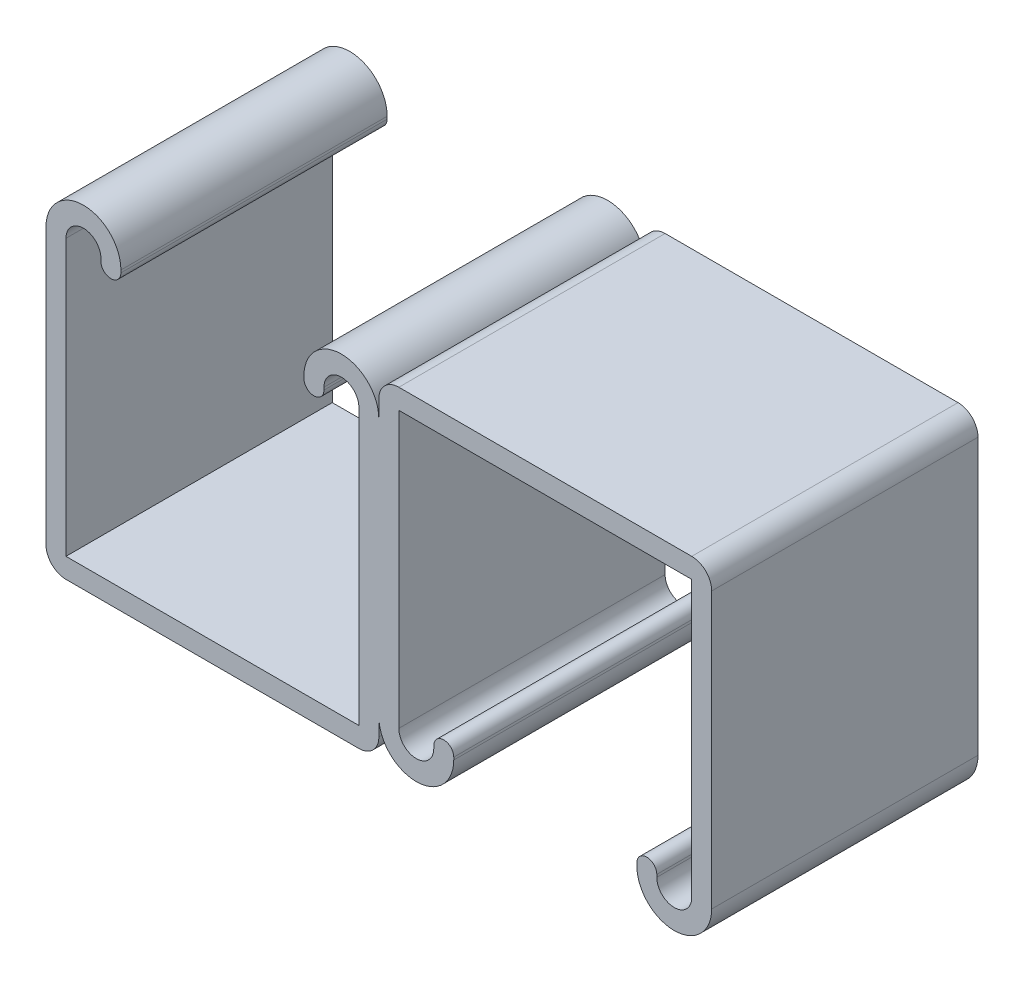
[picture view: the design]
ISO-10303-21;
HEADER;
FILE_DESCRIPTION(('STEP AP214'),'2;1');
FILE_NAME('part.step','',(''),(''),'','','');
FILE_SCHEMA(('AUTOMOTIVE_DESIGN { 1 0 10303 214 1 1 1 1 }'));
ENDSEC;
DATA;
#1=APPLICATION_CONTEXT('core data for automotive mechanical design processes');
#2=APPLICATION_PROTOCOL_DEFINITION('international standard','automotive_design',2000,#1);
#3=PRODUCT_CONTEXT('',#1,'mechanical');
#4=PRODUCT('Part','Part','',(#3));
#5=PRODUCT_RELATED_PRODUCT_CATEGORY('part','',(#4));
#6=PRODUCT_DEFINITION_FORMATION('','',#4);
#7=PRODUCT_DEFINITION_CONTEXT('part definition',#1,'design');
#8=PRODUCT_DEFINITION('design','',#6,#7);
#9=PRODUCT_DEFINITION_SHAPE('','',#8);
#10=(LENGTH_UNIT() NAMED_UNIT(*) SI_UNIT(.MILLI.,.METRE.));
#11=(NAMED_UNIT(*) PLANE_ANGLE_UNIT() SI_UNIT($,.RADIAN.));
#12=(NAMED_UNIT(*) SI_UNIT($,.STERADIAN.) SOLID_ANGLE_UNIT());
#13=UNCERTAINTY_MEASURE_WITH_UNIT(LENGTH_MEASURE(1.E-05),#10,'distance_accuracy_value','');
#14=(GEOMETRIC_REPRESENTATION_CONTEXT(3) GLOBAL_UNCERTAINTY_ASSIGNED_CONTEXT((#13)) GLOBAL_UNIT_ASSIGNED_CONTEXT((#10,
#11,#12)) REPRESENTATION_CONTEXT('',''));
#15=CARTESIAN_POINT('',(0.,0.,0.));
#16=DIRECTION('',(0.,0.,1.));
#17=DIRECTION('',(1.,0.,0.));
#18=AXIS2_PLACEMENT_3D('',#15,#16,#17);
#19=CARTESIAN_POINT('',(-28.178125,12.303125,12.7));
#20=DIRECTION('',(0.,0.,-1.));
#21=DIRECTION('',(-1.,0.,0.));
#22=AXIS2_PLACEMENT_3D('',#19,#20,#21);
#23=CYLINDRICAL_SURFACE('',#22,3.571875);
#24=CARTESIAN_POINT('',(-28.178125,12.303125,-12.7));
#25=DIRECTION('',(0.,0.,1.));
#26=DIRECTION('',(-1.,0.,0.));
#27=AXIS2_PLACEMENT_3D('',#24,#25,#26);
#28=CIRCLE('',#27,3.571875);
#29=CARTESIAN_POINT('',(-24.60625,12.303125,-12.7));
#30=VERTEX_POINT('',#29);
#31=CARTESIAN_POINT('',(-31.75,12.303125,-12.7));
#32=VERTEX_POINT('',#31);
#33=EDGE_CURVE('E300',#30,#32,#28,.T.);
#34=ORIENTED_EDGE('',*,*,#33,.T.);
#35=DIRECTION('',(0.,0.,-1.));
#36=VECTOR('',#35,1.);
#37=CARTESIAN_POINT('',(-31.75,12.303125,12.7));
#38=LINE('',#37,#36);
#39=CARTESIAN_POINT('',(-31.75,12.303125,12.7));
#40=VERTEX_POINT('',#39);
#41=EDGE_CURVE('E11',#40,#32,#38,.T.);
#42=ORIENTED_EDGE('',*,*,#41,.F.);
#43=CARTESIAN_POINT('',(-28.178125,12.303125,12.7));
#44=DIRECTION('',(0.,0.,1.));
#45=DIRECTION('',(-1.,0.,0.));
#46=AXIS2_PLACEMENT_3D('',#43,#44,#45);
#47=CIRCLE('',#46,3.571875);
#48=CARTESIAN_POINT('',(-24.60625,12.303125,12.7));
#49=VERTEX_POINT('',#48);
#50=EDGE_CURVE('E306',#49,#40,#47,.T.);
#51=ORIENTED_EDGE('',*,*,#50,.F.);
#52=DIRECTION('',(0.,0.,-1.));
#53=VECTOR('',#52,1.);
#54=CARTESIAN_POINT('',(-24.60625,12.303125,12.7));
#55=LINE('',#54,#53);
#56=EDGE_CURVE('E341',#49,#30,#55,.T.);
#57=ORIENTED_EDGE('',*,*,#56,.T.);
#58=EDGE_LOOP('',(#34,#42,#51,#57));
#59=FACE_BOUND('',#58,.T.);
#60=ADVANCED_FACE('F39',(#59),#23,.T.);
#61=CARTESIAN_POINT('',(-31.75,12.303125,12.7));
#62=DIRECTION('',(1.,0.,0.));
#63=DIRECTION('',(0.,1.,0.));
#64=AXIS2_PLACEMENT_3D('',#61,#62,#63);
#65=PLANE('',#64);
#66=DIRECTION('',(0.,-1.,0.));
#67=VECTOR('',#66,1.);
#68=CARTESIAN_POINT('',(-31.75,12.303125,-12.7));
#69=LINE('',#68,#67);
#70=CARTESIAN_POINT('',(-31.75,-13.97,-12.7));
#71=VERTEX_POINT('',#70);
#72=EDGE_CURVE('E297',#32,#71,#69,.T.);
#73=ORIENTED_EDGE('',*,*,#72,.T.);
#74=DIRECTION('',(0.,0.,-1.));
#75=VECTOR('',#74,1.);
#76=CARTESIAN_POINT('',(-31.75,-13.97,12.7));
#77=LINE('',#76,#75);
#78=CARTESIAN_POINT('',(-31.75,-13.97,12.7));
#79=VERTEX_POINT('',#78);
#80=EDGE_CURVE('E46',#79,#71,#77,.T.);
#81=ORIENTED_EDGE('',*,*,#80,.F.);
#82=DIRECTION('',(0.,-1.,0.));
#83=VECTOR('',#82,1.);
#84=CARTESIAN_POINT('',(-31.75,12.303125,12.7));
#85=LINE('',#84,#83);
#86=EDGE_CURVE('E308',#40,#79,#85,.T.);
#87=ORIENTED_EDGE('',*,*,#86,.F.);
#88=ORIENTED_EDGE('',*,*,#41,.T.);
#89=EDGE_LOOP('',(#73,#81,#87,#88));
#90=FACE_BOUND('',#89,.T.);
#91=ADVANCED_FACE('F443',(#90),#65,.F.);
#92=CARTESIAN_POINT('',(-29.845,-13.97,12.7));
#93=DIRECTION('',(0.,0.,-1.));
#94=DIRECTION('',(-1.,0.,0.));
#95=AXIS2_PLACEMENT_3D('',#92,#93,#94);
#96=CYLINDRICAL_SURFACE('',#95,1.90499999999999);
#97=CARTESIAN_POINT('',(-29.845,-13.97,-12.7));
#98=DIRECTION('',(0.,0.,1.));
#99=DIRECTION('',(-1.,0.,0.));
#100=AXIS2_PLACEMENT_3D('',#97,#98,#99);
#101=CIRCLE('',#100,1.90499999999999);
#102=CARTESIAN_POINT('',(-29.845,-15.875,-12.7));
#103=VERTEX_POINT('',#102);
#104=EDGE_CURVE('E342',#71,#103,#101,.T.);
#105=ORIENTED_EDGE('',*,*,#104,.T.);
#106=DIRECTION('',(0.,0.,-1.));
#107=VECTOR('',#106,1.);
#108=CARTESIAN_POINT('',(-29.845,-15.875,12.7));
#109=LINE('',#108,#107);
#110=CARTESIAN_POINT('',(-29.845,-15.875,12.7));
#111=VERTEX_POINT('',#110);
#112=EDGE_CURVE('E419',#111,#103,#109,.T.);
#113=ORIENTED_EDGE('',*,*,#112,.F.);
#114=CARTESIAN_POINT('',(-29.845,-13.97,12.7));
#115=DIRECTION('',(0.,0.,1.));
#116=DIRECTION('',(-1.,0.,0.));
#117=AXIS2_PLACEMENT_3D('',#114,#115,#116);
#118=CIRCLE('',#117,1.90499999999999);
#119=EDGE_CURVE('E311',#79,#111,#118,.T.);
#120=ORIENTED_EDGE('',*,*,#119,.F.);
#121=ORIENTED_EDGE('',*,*,#80,.T.);
#122=EDGE_LOOP('',(#105,#113,#120,#121));
#123=FACE_BOUND('',#122,.T.);
#124=ADVANCED_FACE('F424',(#123),#96,.T.);
#125=CARTESIAN_POINT('',(-29.845,-15.875,12.7));
#126=DIRECTION('',(0.,1.,0.));
#127=DIRECTION('',(0.,0.,1.));
#128=AXIS2_PLACEMENT_3D('',#125,#126,#127);
#129=PLANE('',#128);
#130=DIRECTION('',(1.,0.,0.));
#131=VECTOR('',#130,1.);
#132=CARTESIAN_POINT('',(-29.845,-15.875,-12.7));
#133=LINE('',#132,#131);
#134=CARTESIAN_POINT('',(-1.905,-15.875,-12.7));
#135=VERTEX_POINT('',#134);
#136=EDGE_CURVE('E350',#103,#135,#133,.T.);
#137=ORIENTED_EDGE('',*,*,#136,.T.);
#138=DIRECTION('',(0.,0.,-1.));
#139=VECTOR('',#138,1.);
#140=CARTESIAN_POINT('',(-1.905,-15.875,12.7));
#141=LINE('',#140,#139);
#142=CARTESIAN_POINT('',(-1.905,-15.875,12.7));
#143=VERTEX_POINT('',#142);
#144=EDGE_CURVE('E411',#143,#135,#141,.T.);
#145=ORIENTED_EDGE('',*,*,#144,.F.);
#146=DIRECTION('',(1.,0.,0.));
#147=VECTOR('',#146,1.);
#148=CARTESIAN_POINT('',(-29.845,-15.875,12.7));
#149=LINE('',#148,#147);
#150=EDGE_CURVE('E312',#111,#143,#149,.T.);
#151=ORIENTED_EDGE('',*,*,#150,.F.);
#152=ORIENTED_EDGE('',*,*,#112,.T.);
#153=EDGE_LOOP('',(#137,#145,#151,#152));
#154=FACE_BOUND('',#153,.T.);
#155=ADVANCED_FACE('F434',(#154),#129,.F.);
#156=CARTESIAN_POINT('',(-1.905,-13.97,12.7));
#157=DIRECTION('',(0.,0.,-1.));
#158=DIRECTION('',(-1.,0.,0.));
#159=AXIS2_PLACEMENT_3D('',#156,#157,#158);
#160=CYLINDRICAL_SURFACE('',#159,1.905);
#161=CARTESIAN_POINT('',(-1.905,-13.97,-12.7));
#162=DIRECTION('',(0.,0.,1.));
#163=DIRECTION('',(1.,0.,0.));
#164=AXIS2_PLACEMENT_3D('',#161,#162,#163);
#165=CIRCLE('',#164,1.905);
#166=CARTESIAN_POINT('',(0.,-13.97,-12.7));
#167=VERTEX_POINT('',#166);
#168=EDGE_CURVE('E349',#135,#167,#165,.T.);
#169=ORIENTED_EDGE('',*,*,#168,.T.);
#170=DIRECTION('',(0.,0.,-1.));
#171=VECTOR('',#170,1.);
#172=CARTESIAN_POINT('',(0.,-13.97,12.7));
#173=LINE('',#172,#171);
#174=CARTESIAN_POINT('',(0.,-13.97,12.7));
#175=VERTEX_POINT('',#174);
#176=EDGE_CURVE('E413',#175,#167,#173,.T.);
#177=ORIENTED_EDGE('',*,*,#176,.F.);
#178=CARTESIAN_POINT('',(-1.905,-13.97,12.7));
#179=DIRECTION('',(0.,0.,1.));
#180=DIRECTION('',(1.,0.,0.));
#181=AXIS2_PLACEMENT_3D('',#178,#179,#180);
#182=CIRCLE('',#181,1.905);
#183=EDGE_CURVE('E314',#143,#175,#182,.T.);
#184=ORIENTED_EDGE('',*,*,#183,.F.);
#185=ORIENTED_EDGE('',*,*,#144,.T.);
#186=EDGE_LOOP('',(#169,#177,#184,#185));
#187=FACE_BOUND('',#186,.T.);
#188=ADVANCED_FACE('F437',(#187),#160,.T.);
#189=CARTESIAN_POINT('',(0.,-13.97,12.7));
#190=DIRECTION('',(-1.,0.,0.));
#191=DIRECTION('',(0.,0.,1.));
#192=AXIS2_PLACEMENT_3D('',#189,#190,#191);
#193=PLANE('',#192);
#194=DIRECTION('',(0.,1.,0.));
#195=VECTOR('',#194,1.);
#196=CARTESIAN_POINT('',(0.,-13.97,-12.7));
#197=LINE('',#196,#195);
#198=CARTESIAN_POINT('',(0.,-12.303125,-12.7));
#199=VERTEX_POINT('',#198);
#200=EDGE_CURVE('E59',#167,#199,#197,.T.);
#201=ORIENTED_EDGE('',*,*,#200,.T.);
#202=DIRECTION('',(0.,0.,-1.));
#203=VECTOR('',#202,1.);
#204=CARTESIAN_POINT('',(0.,-12.303125,12.7));
#205=LINE('',#204,#203);
#206=CARTESIAN_POINT('',(0.,-12.303125,12.7));
#207=VERTEX_POINT('',#206);
#208=EDGE_CURVE('E52',#207,#199,#205,.T.);
#209=ORIENTED_EDGE('',*,*,#208,.F.);
#210=DIRECTION('',(0.,1.,0.));
#211=VECTOR('',#210,1.);
#212=CARTESIAN_POINT('',(0.,-13.97,12.7));
#213=LINE('',#212,#211);
#214=EDGE_CURVE('E320',#175,#207,#213,.T.);
#215=ORIENTED_EDGE('',*,*,#214,.F.);
#216=ORIENTED_EDGE('',*,*,#176,.T.);
#217=EDGE_LOOP('',(#201,#209,#215,#216));
#218=FACE_BOUND('',#217,.T.);
#219=ADVANCED_FACE('F650',(#218),#193,.F.);
#220=CARTESIAN_POINT('',(-3.571875,12.303125,12.7));
#221=DIRECTION('',(0.,0.,-1.));
#222=DIRECTION('',(-1.,0.,0.));
#223=AXIS2_PLACEMENT_3D('',#220,#221,#222);
#224=CYLINDRICAL_SURFACE('',#223,3.571875);
#225=CARTESIAN_POINT('',(-3.571875,12.303125,-12.7));
#226=DIRECTION('',(0.,0.,1.));
#227=DIRECTION('',(1.,0.,0.));
#228=AXIS2_PLACEMENT_3D('',#225,#226,#227);
#229=CIRCLE('',#228,3.571875);
#230=CARTESIAN_POINT('',(0.,12.303125,-12.7));
#231=VERTEX_POINT('',#230);
#232=CARTESIAN_POINT('',(-7.14375,12.303125,-12.7));
#233=VERTEX_POINT('',#232);
#234=EDGE_CURVE('E355',#231,#233,#229,.T.);
#235=ORIENTED_EDGE('',*,*,#234,.T.);
#236=DIRECTION('',(0.,0.,-1.));
#237=VECTOR('',#236,1.);
#238=CARTESIAN_POINT('',(-7.14375,12.303125,12.7));
#239=LINE('',#238,#237);
#240=CARTESIAN_POINT('',(-7.14375,12.303125,12.7));
#241=VERTEX_POINT('',#240);
#242=EDGE_CURVE('E406',#241,#233,#239,.T.);
#243=ORIENTED_EDGE('',*,*,#242,.F.);
#244=CARTESIAN_POINT('',(-3.571875,12.303125,12.7));
#245=DIRECTION('',(0.,0.,1.));
#246=DIRECTION('',(1.,0.,0.));
#247=AXIS2_PLACEMENT_3D('',#244,#245,#246);
#248=CIRCLE('',#247,3.571875);
#249=CARTESIAN_POINT('',(0.,12.303125,12.7));
#250=VERTEX_POINT('',#249);
#251=EDGE_CURVE('E316',#250,#241,#248,.T.);
#252=ORIENTED_EDGE('',*,*,#251,.F.);
#253=DIRECTION('',(0.,0.,-1.));
#254=VECTOR('',#253,1.);
#255=CARTESIAN_POINT('',(0.,12.303125,12.7));
#256=LINE('',#255,#254);
#257=EDGE_CURVE('E407',#250,#231,#256,.T.);
#258=ORIENTED_EDGE('',*,*,#257,.T.);
#259=EDGE_LOOP('',(#235,#243,#252,#258));
#260=FACE_BOUND('',#259,.T.);
#261=ADVANCED_FACE('F503',(#260),#224,.T.);
#262=CARTESIAN_POINT('',(-7.14375,12.303125,12.7));
#263=DIRECTION('',(1.,0.,0.));
#264=DIRECTION('',(0.,1.,0.));
#265=AXIS2_PLACEMENT_3D('',#262,#263,#264);
#266=PLANE('',#265);
#267=DIRECTION('',(0.,-1.,0.));
#268=VECTOR('',#267,1.);
#269=CARTESIAN_POINT('',(-7.14375,12.303125,-12.7));
#270=LINE('',#269,#268);
#271=CARTESIAN_POINT('',(-7.14375,12.065,-12.7));
#272=VERTEX_POINT('',#271);
#273=EDGE_CURVE('E351',#233,#272,#270,.T.);
#274=ORIENTED_EDGE('',*,*,#273,.T.);
#275=DIRECTION('',(0.,0.,-1.));
#276=VECTOR('',#275,1.);
#277=CARTESIAN_POINT('',(-7.14375,12.065,12.7));
#278=LINE('',#277,#276);
#279=CARTESIAN_POINT('',(-7.14375,12.065,12.7));
#280=VERTEX_POINT('',#279);
#281=EDGE_CURVE('E404',#280,#272,#278,.T.);
#282=ORIENTED_EDGE('',*,*,#281,.F.);
#283=DIRECTION('',(0.,-1.,0.));
#284=VECTOR('',#283,1.);
#285=CARTESIAN_POINT('',(-7.14375,12.303125,12.7));
#286=LINE('',#285,#284);
#287=EDGE_CURVE('E324',#241,#280,#286,.T.);
#288=ORIENTED_EDGE('',*,*,#287,.F.);
#289=ORIENTED_EDGE('',*,*,#242,.T.);
#290=EDGE_LOOP('',(#274,#282,#288,#289));
#291=FACE_BOUND('',#290,.T.);
#292=ADVANCED_FACE('F499',(#291),#266,.F.);
#293=CARTESIAN_POINT('',(-6.19125,12.065,12.7));
#294=DIRECTION('',(0.,0.,-1.));
#295=DIRECTION('',(-1.,0.,0.));
#296=AXIS2_PLACEMENT_3D('',#293,#294,#295);
#297=CYLINDRICAL_SURFACE('',#296,0.9525);
#298=CARTESIAN_POINT('',(-6.19125,12.065,-12.7));
#299=DIRECTION('',(0.,0.,1.));
#300=DIRECTION('',(1.,0.,0.));
#301=AXIS2_PLACEMENT_3D('',#298,#299,#300);
#302=CIRCLE('',#301,0.9525);
#303=CARTESIAN_POINT('',(-5.23875,12.065,-12.7));
#304=VERTEX_POINT('',#303);
#305=EDGE_CURVE('E358',#272,#304,#302,.T.);
#306=ORIENTED_EDGE('',*,*,#305,.T.);
#307=DIRECTION('',(0.,0.,-1.));
#308=VECTOR('',#307,1.);
#309=CARTESIAN_POINT('',(-5.23875,12.065,12.7));
#310=LINE('',#309,#308);
#311=CARTESIAN_POINT('',(-5.23875,12.065,12.7));
#312=VERTEX_POINT('',#311);
#313=EDGE_CURVE('E402',#312,#304,#310,.T.);
#314=ORIENTED_EDGE('',*,*,#313,.F.);
#315=CARTESIAN_POINT('',(-6.19125,12.065,12.7));
#316=DIRECTION('',(0.,0.,1.));
#317=DIRECTION('',(1.,0.,0.));
#318=AXIS2_PLACEMENT_3D('',#315,#316,#317);
#319=CIRCLE('',#318,0.9525);
#320=EDGE_CURVE('E325',#280,#312,#319,.T.);
#321=ORIENTED_EDGE('',*,*,#320,.F.);
#322=ORIENTED_EDGE('',*,*,#281,.T.);
#323=EDGE_LOOP('',(#306,#314,#321,#322));
#324=FACE_BOUND('',#323,.T.);
#325=ADVANCED_FACE('F492',(#324),#297,.T.);
#326=CARTESIAN_POINT('',(-5.23875,12.303125,12.7));
#327=DIRECTION('',(-1.,0.,0.));
#328=DIRECTION('',(0.,-1.,0.));
#329=AXIS2_PLACEMENT_3D('',#326,#327,#328);
#330=PLANE('',#329);
#331=DIRECTION('',(0.,1.,0.));
#332=VECTOR('',#331,1.);
#333=CARTESIAN_POINT('',(-5.23875,12.303125,-12.7));
#334=LINE('',#333,#332);
#335=CARTESIAN_POINT('',(-5.23875,12.303125,-12.7));
#336=VERTEX_POINT('',#335);
#337=EDGE_CURVE('E356',#304,#336,#334,.T.);
#338=ORIENTED_EDGE('',*,*,#337,.T.);
#339=DIRECTION('',(0.,0.,-1.));
#340=VECTOR('',#339,1.);
#341=CARTESIAN_POINT('',(-5.23875,12.303125,12.7));
#342=LINE('',#341,#340);
#343=CARTESIAN_POINT('',(-5.23875,12.303125,12.7));
#344=VERTEX_POINT('',#343);
#345=EDGE_CURVE('E399',#344,#336,#342,.T.);
#346=ORIENTED_EDGE('',*,*,#345,.F.);
#347=DIRECTION('',(0.,1.,0.));
#348=VECTOR('',#347,1.);
#349=CARTESIAN_POINT('',(-5.23875,12.303125,12.7));
#350=LINE('',#349,#348);
#351=EDGE_CURVE('E322',#312,#344,#350,.T.);
#352=ORIENTED_EDGE('',*,*,#351,.F.);
#353=ORIENTED_EDGE('',*,*,#313,.T.);
#354=EDGE_LOOP('',(#338,#346,#352,#353));
#355=FACE_BOUND('',#354,.T.);
#356=ADVANCED_FACE('F489',(#355),#330,.F.);
#357=CARTESIAN_POINT('',(-3.571875,12.303125,12.7));
#358=DIRECTION('',(0.,0.,-1.));
#359=DIRECTION('',(-1.,0.,0.));
#360=AXIS2_PLACEMENT_3D('',#357,#358,#359);
#361=CYLINDRICAL_SURFACE('',#360,1.666875);
#362=CARTESIAN_POINT('',(-3.571875,12.303125,-12.7));
#363=DIRECTION('',(0.,0.,-1.));
#364=DIRECTION('',(1.,0.,0.));
#365=AXIS2_PLACEMENT_3D('',#362,#363,#364);
#366=CIRCLE('',#365,1.666875);
#367=CARTESIAN_POINT('',(-1.905,12.303125,-12.7));
#368=VERTEX_POINT('',#367);
#369=EDGE_CURVE('E359',#336,#368,#366,.T.);
#370=ORIENTED_EDGE('',*,*,#369,.T.);
#371=DIRECTION('',(0.,0.,-1.));
#372=VECTOR('',#371,1.);
#373=CARTESIAN_POINT('',(-1.905,12.303125,12.7));
#374=LINE('',#373,#372);
#375=CARTESIAN_POINT('',(-1.905,12.303125,12.7));
#376=VERTEX_POINT('',#375);
#377=EDGE_CURVE('E391',#376,#368,#374,.T.);
#378=ORIENTED_EDGE('',*,*,#377,.F.);
#379=CARTESIAN_POINT('',(-3.571875,12.303125,12.7));
#380=DIRECTION('',(0.,0.,-1.));
#381=DIRECTION('',(1.,0.,0.));
#382=AXIS2_PLACEMENT_3D('',#379,#380,#381);
#383=CIRCLE('',#382,1.666875);
#384=EDGE_CURVE('E330',#344,#376,#383,.T.);
#385=ORIENTED_EDGE('',*,*,#384,.F.);
#386=ORIENTED_EDGE('',*,*,#345,.T.);
#387=EDGE_LOOP('',(#370,#378,#385,#386));
#388=FACE_BOUND('',#387,.T.);
#389=ADVANCED_FACE('F488',(#388),#361,.F.);
#390=CARTESIAN_POINT('',(-1.905,-13.97,12.7));
#391=DIRECTION('',(1.,0.,0.));
#392=DIRECTION('',(0.,0.,-1.));
#393=AXIS2_PLACEMENT_3D('',#390,#391,#392);
#394=PLANE('',#393);
#395=DIRECTION('',(0.,-1.,0.));
#396=VECTOR('',#395,1.);
#397=CARTESIAN_POINT('',(-1.905,-13.97,-12.7));
#398=LINE('',#397,#396);
#399=CARTESIAN_POINT('',(-1.905,-13.97,-12.7));
#400=VERTEX_POINT('',#399);
#401=EDGE_CURVE('E365',#368,#400,#398,.T.);
#402=ORIENTED_EDGE('',*,*,#401,.T.);
#403=DIRECTION('',(0.,0.,-1.));
#404=VECTOR('',#403,1.);
#405=CARTESIAN_POINT('',(-1.905,-13.97,12.7));
#406=LINE('',#405,#404);
#407=CARTESIAN_POINT('',(-1.905,-13.97,12.7));
#408=VERTEX_POINT('',#407);
#409=EDGE_CURVE('E395',#408,#400,#406,.T.);
#410=ORIENTED_EDGE('',*,*,#409,.F.);
#411=DIRECTION('',(0.,-1.,0.));
#412=VECTOR('',#411,1.);
#413=CARTESIAN_POINT('',(-1.905,-13.97,12.7));
#414=LINE('',#413,#412);
#415=EDGE_CURVE('E329',#376,#408,#414,.T.);
#416=ORIENTED_EDGE('',*,*,#415,.F.);
#417=ORIENTED_EDGE('',*,*,#377,.T.);
#418=EDGE_LOOP('',(#402,#410,#416,#417));
#419=FACE_BOUND('',#418,.T.);
#420=ADVANCED_FACE('F482',(#419),#394,.F.);
#421=CARTESIAN_POINT('',(-29.845,-13.97,12.7));
#422=DIRECTION('',(0.,-1.,0.));
#423=DIRECTION('',(0.,0.,-1.));
#424=AXIS2_PLACEMENT_3D('',#421,#422,#423);
#425=PLANE('',#424);
#426=DIRECTION('',(-1.,0.,0.));
#427=VECTOR('',#426,1.);
#428=CARTESIAN_POINT('',(-29.845,-13.97,-12.7));
#429=LINE('',#428,#427);
#430=CARTESIAN_POINT('',(-29.845,-13.97,-12.7));
#431=VERTEX_POINT('',#430);
#432=EDGE_CURVE('E364',#400,#431,#429,.T.);
#433=ORIENTED_EDGE('',*,*,#432,.T.);
#434=DIRECTION('',(0.,0.,-1.));
#435=VECTOR('',#434,1.);
#436=CARTESIAN_POINT('',(-29.845,-13.97,12.7));
#437=LINE('',#436,#435);
#438=CARTESIAN_POINT('',(-29.845,-13.97,12.7));
#439=VERTEX_POINT('',#438);
#440=EDGE_CURVE('E388',#439,#431,#437,.T.);
#441=ORIENTED_EDGE('',*,*,#440,.F.);
#442=DIRECTION('',(-1.,0.,0.));
#443=VECTOR('',#442,1.);
#444=CARTESIAN_POINT('',(-29.845,-13.97,12.7));
#445=LINE('',#444,#443);
#446=EDGE_CURVE('E332',#408,#439,#445,.T.);
#447=ORIENTED_EDGE('',*,*,#446,.F.);
#448=ORIENTED_EDGE('',*,*,#409,.T.);
#449=EDGE_LOOP('',(#433,#441,#447,#448));
#450=FACE_BOUND('',#449,.T.);
#451=ADVANCED_FACE('F472',(#450),#425,.F.);
#452=CARTESIAN_POINT('',(-29.845,12.303125,12.7));
#453=DIRECTION('',(-1.,0.,0.));
#454=DIRECTION('',(0.,-1.,0.));
#455=AXIS2_PLACEMENT_3D('',#452,#453,#454);
#456=PLANE('',#455);
#457=DIRECTION('',(0.,1.,0.));
#458=VECTOR('',#457,1.);
#459=CARTESIAN_POINT('',(-29.845,12.303125,-12.7));
#460=LINE('',#459,#458);
#461=CARTESIAN_POINT('',(-29.845,12.303125,-12.7));
#462=VERTEX_POINT('',#461);
#463=EDGE_CURVE('E366',#431,#462,#460,.T.);
#464=ORIENTED_EDGE('',*,*,#463,.T.);
#465=DIRECTION('',(0.,0.,-1.));
#466=VECTOR('',#465,1.);
#467=CARTESIAN_POINT('',(-29.845,12.303125,12.7));
#468=LINE('',#467,#466);
#469=CARTESIAN_POINT('',(-29.845,12.303125,12.7));
#470=VERTEX_POINT('',#469);
#471=EDGE_CURVE('E389',#470,#462,#468,.T.);
#472=ORIENTED_EDGE('',*,*,#471,.F.);
#473=DIRECTION('',(0.,1.,0.));
#474=VECTOR('',#473,1.);
#475=CARTESIAN_POINT('',(-29.845,12.303125,12.7));
#476=LINE('',#475,#474);
#477=EDGE_CURVE('E334',#439,#470,#476,.T.);
#478=ORIENTED_EDGE('',*,*,#477,.F.);
#479=ORIENTED_EDGE('',*,*,#440,.T.);
#480=EDGE_LOOP('',(#464,#472,#478,#479));
#481=FACE_BOUND('',#480,.T.);
#482=ADVANCED_FACE('F474',(#481),#456,.F.);
#483=CARTESIAN_POINT('',(-28.178125,12.303125,12.7));
#484=DIRECTION('',(0.,0.,-1.));
#485=DIRECTION('',(-1.,0.,0.));
#486=AXIS2_PLACEMENT_3D('',#483,#484,#485);
#487=CYLINDRICAL_SURFACE('',#486,1.666875);
#488=CARTESIAN_POINT('',(-28.178125,12.303125,-12.7));
#489=DIRECTION('',(0.,0.,-1.));
#490=DIRECTION('',(-1.,0.,0.));
#491=AXIS2_PLACEMENT_3D('',#488,#489,#490);
#492=CIRCLE('',#491,1.666875);
#493=CARTESIAN_POINT('',(-26.51125,12.303125,-12.7));
#494=VERTEX_POINT('',#493);
#495=EDGE_CURVE('E368',#462,#494,#492,.T.);
#496=ORIENTED_EDGE('',*,*,#495,.T.);
#497=DIRECTION('',(0.,0.,-1.));
#498=VECTOR('',#497,1.);
#499=CARTESIAN_POINT('',(-26.51125,12.303125,12.7));
#500=LINE('',#499,#498);
#501=CARTESIAN_POINT('',(-26.51125,12.303125,12.7));
#502=VERTEX_POINT('',#501);
#503=EDGE_CURVE('E384',#502,#494,#500,.T.);
#504=ORIENTED_EDGE('',*,*,#503,.F.);
#505=CARTESIAN_POINT('',(-28.178125,12.303125,12.7));
#506=DIRECTION('',(0.,0.,-1.));
#507=DIRECTION('',(-1.,0.,0.));
#508=AXIS2_PLACEMENT_3D('',#505,#506,#507);
#509=CIRCLE('',#508,1.666875);
#510=EDGE_CURVE('E333',#470,#502,#509,.T.);
#511=ORIENTED_EDGE('',*,*,#510,.F.);
#512=ORIENTED_EDGE('',*,*,#471,.T.);
#513=EDGE_LOOP('',(#496,#504,#511,#512));
#514=FACE_BOUND('',#513,.T.);
#515=ADVANCED_FACE('F467',(#514),#487,.F.);
#516=CARTESIAN_POINT('',(-26.51125,12.303125,12.7));
#517=DIRECTION('',(1.,0.,0.));
#518=DIRECTION('',(0.,1.,0.));
#519=AXIS2_PLACEMENT_3D('',#516,#517,#518);
#520=PLANE('',#519);
#521=DIRECTION('',(0.,-1.,0.));
#522=VECTOR('',#521,1.);
#523=CARTESIAN_POINT('',(-26.51125,12.303125,-12.7));
#524=LINE('',#523,#522);
#525=CARTESIAN_POINT('',(-26.51125,12.065,-12.7));
#526=VERTEX_POINT('',#525);
#527=EDGE_CURVE('E369',#494,#526,#524,.T.);
#528=ORIENTED_EDGE('',*,*,#527,.T.);
#529=DIRECTION('',(0.,0.,-1.));
#530=VECTOR('',#529,1.);
#531=CARTESIAN_POINT('',(-26.51125,12.065,12.7));
#532=LINE('',#531,#530);
#533=CARTESIAN_POINT('',(-26.51125,12.065,12.7));
#534=VERTEX_POINT('',#533);
#535=EDGE_CURVE('E379',#534,#526,#532,.T.);
#536=ORIENTED_EDGE('',*,*,#535,.F.);
#537=DIRECTION('',(0.,-1.,0.));
#538=VECTOR('',#537,1.);
#539=CARTESIAN_POINT('',(-26.51125,12.303125,12.7));
#540=LINE('',#539,#538);
#541=EDGE_CURVE('E340',#502,#534,#540,.T.);
#542=ORIENTED_EDGE('',*,*,#541,.F.);
#543=ORIENTED_EDGE('',*,*,#503,.T.);
#544=EDGE_LOOP('',(#528,#536,#542,#543));
#545=FACE_BOUND('',#544,.T.);
#546=ADVANCED_FACE('F456',(#545),#520,.F.);
#547=CARTESIAN_POINT('',(-25.55875,12.065,12.7));
#548=DIRECTION('',(0.,0.,-1.));
#549=DIRECTION('',(-1.,0.,0.));
#550=AXIS2_PLACEMENT_3D('',#547,#548,#549);
#551=CYLINDRICAL_SURFACE('',#550,0.952500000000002);
#552=CARTESIAN_POINT('',(-25.55875,12.065,-12.7));
#553=DIRECTION('',(0.,0.,1.));
#554=DIRECTION('',(-1.,0.,0.));
#555=AXIS2_PLACEMENT_3D('',#552,#553,#554);
#556=CIRCLE('',#555,0.952500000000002);
#557=CARTESIAN_POINT('',(-24.60625,12.065,-12.7));
#558=VERTEX_POINT('',#557);
#559=EDGE_CURVE('E375',#526,#558,#556,.T.);
#560=ORIENTED_EDGE('',*,*,#559,.T.);
#561=DIRECTION('',(0.,0.,-1.));
#562=VECTOR('',#561,1.);
#563=CARTESIAN_POINT('',(-24.60625,12.065,12.7));
#564=LINE('',#563,#562);
#565=CARTESIAN_POINT('',(-24.60625,12.065,12.7));
#566=VERTEX_POINT('',#565);
#567=EDGE_CURVE('E380',#566,#558,#564,.T.);
#568=ORIENTED_EDGE('',*,*,#567,.F.);
#569=CARTESIAN_POINT('',(-25.55875,12.065,12.7));
#570=DIRECTION('',(0.,0.,1.));
#571=DIRECTION('',(-1.,0.,0.));
#572=AXIS2_PLACEMENT_3D('',#569,#570,#571);
#573=CIRCLE('',#572,0.952500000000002);
#574=EDGE_CURVE('E339',#534,#566,#573,.T.);
#575=ORIENTED_EDGE('',*,*,#574,.F.);
#576=ORIENTED_EDGE('',*,*,#535,.T.);
#577=EDGE_LOOP('',(#560,#568,#575,#576));
#578=FACE_BOUND('',#577,.T.);
#579=ADVANCED_FACE('F457',(#578),#551,.T.);
#580=CARTESIAN_POINT('',(-24.60625,12.303125,12.7));
#581=DIRECTION('',(-1.,0.,0.));
#582=DIRECTION('',(0.,-1.,0.));
#583=AXIS2_PLACEMENT_3D('',#580,#581,#582);
#584=PLANE('',#583);
#585=DIRECTION('',(0.,1.,0.));
#586=VECTOR('',#585,1.);
#587=CARTESIAN_POINT('',(-24.60625,12.303125,-12.7));
#588=LINE('',#587,#586);
#589=EDGE_CURVE('E307',#558,#30,#588,.T.);
#590=ORIENTED_EDGE('',*,*,#589,.T.);
#591=ORIENTED_EDGE('',*,*,#56,.F.);
#592=DIRECTION('',(0.,1.,0.));
#593=VECTOR('',#592,1.);
#594=CARTESIAN_POINT('',(-24.60625,12.303125,12.7));
#595=LINE('',#594,#593);
#596=EDGE_CURVE('E344',#566,#49,#595,.T.);
#597=ORIENTED_EDGE('',*,*,#596,.F.);
#598=ORIENTED_EDGE('',*,*,#567,.T.);
#599=EDGE_LOOP('',(#590,#591,#597,#598));
#600=FACE_BOUND('',#599,.T.);
#601=ADVANCED_FACE('F454',(#600),#584,.F.);
#602=CARTESIAN_POINT('',(-28.178125,12.303125,12.7));
#603=DIRECTION('',(0.,0.,-1.));
#604=DIRECTION('',(-1.,0.,0.));
#605=AXIS2_PLACEMENT_3D('',#602,#603,#604);
#606=PLANE('',#605);
#607=ORIENTED_EDGE('',*,*,#50,.T.);
#608=ORIENTED_EDGE('',*,*,#86,.T.);
#609=ORIENTED_EDGE('',*,*,#119,.T.);
#610=ORIENTED_EDGE('',*,*,#150,.T.);
#611=ORIENTED_EDGE('',*,*,#183,.T.);
#612=ORIENTED_EDGE('',*,*,#214,.T.);
#613=CARTESIAN_POINT('',(3.57187500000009,-12.303125,12.7));
#614=DIRECTION('',(0.,0.,1.));
#615=DIRECTION('',(-1.,0.,0.));
#616=AXIS2_PLACEMENT_3D('',#613,#614,#615);
#617=CIRCLE('',#616,3.571875);
#618=CARTESIAN_POINT('',(7.14375000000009,-12.3031249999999,12.7));
#619=VERTEX_POINT('',#618);
#620=EDGE_CURVE('E617',#207,#619,#617,.T.);
#621=ORIENTED_EDGE('',*,*,#620,.T.);
#622=DIRECTION('',(0.,1.,0.));
#623=VECTOR('',#622,1.);
#624=CARTESIAN_POINT('',(7.14375000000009,-12.3031249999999,12.7));
#625=LINE('',#624,#623);
#626=CARTESIAN_POINT('',(7.14375000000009,-12.065,12.7));
#627=VERTEX_POINT('',#626);
#628=EDGE_CURVE('E613',#619,#627,#625,.T.);
#629=ORIENTED_EDGE('',*,*,#628,.T.);
#630=CARTESIAN_POINT('',(6.19125000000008,-12.065,12.7));
#631=DIRECTION('',(0.,0.,1.));
#632=DIRECTION('',(-1.,0.,0.));
#633=AXIS2_PLACEMENT_3D('',#630,#631,#632);
#634=CIRCLE('',#633,0.9525);
#635=CARTESIAN_POINT('',(5.23875000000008,-12.065,12.7));
#636=VERTEX_POINT('',#635);
#637=EDGE_CURVE('E614',#627,#636,#634,.T.);
#638=ORIENTED_EDGE('',*,*,#637,.T.);
#639=DIRECTION('',(0.,-1.,0.));
#640=VECTOR('',#639,1.);
#641=CARTESIAN_POINT('',(5.23875000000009,-12.303125,12.7));
#642=LINE('',#641,#640);
#643=CARTESIAN_POINT('',(5.23875000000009,-12.303125,12.7));
#644=VERTEX_POINT('',#643);
#645=EDGE_CURVE('E612',#636,#644,#642,.T.);
#646=ORIENTED_EDGE('',*,*,#645,.T.);
#647=CARTESIAN_POINT('',(3.57187500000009,-12.303125,12.7));
#648=DIRECTION('',(0.,0.,-1.));
#649=DIRECTION('',(-1.,0.,0.));
#650=AXIS2_PLACEMENT_3D('',#647,#648,#649);
#651=CIRCLE('',#650,1.666875);
#652=CARTESIAN_POINT('',(1.90500000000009,-12.303125,12.7));
#653=VERTEX_POINT('',#652);
#654=EDGE_CURVE('E609',#644,#653,#651,.T.);
#655=ORIENTED_EDGE('',*,*,#654,.T.);
#656=DIRECTION('',(0.,1.,0.));
#657=VECTOR('',#656,1.);
#658=CARTESIAN_POINT('',(1.9049999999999,13.97,12.7));
#659=LINE('',#658,#657);
#660=CARTESIAN_POINT('',(1.9049999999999,13.97,12.7));
#661=VERTEX_POINT('',#660);
#662=EDGE_CURVE('E610',#653,#661,#659,.T.);
#663=ORIENTED_EDGE('',*,*,#662,.T.);
#664=DIRECTION('',(1.,0.,0.));
#665=VECTOR('',#664,1.);
#666=CARTESIAN_POINT('',(29.8449999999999,13.9700000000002,12.7));
#667=LINE('',#666,#665);
#668=CARTESIAN_POINT('',(29.8449999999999,13.9700000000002,12.7));
#669=VERTEX_POINT('',#668);
#670=EDGE_CURVE('E602',#661,#669,#667,.T.);
#671=ORIENTED_EDGE('',*,*,#670,.T.);
#672=DIRECTION('',(0.,-1.,0.));
#673=VECTOR('',#672,1.);
#674=CARTESIAN_POINT('',(29.8450000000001,-12.3031249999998,12.7));
#675=LINE('',#674,#673);
#676=CARTESIAN_POINT('',(29.8450000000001,-12.3031249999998,12.7));
#677=VERTEX_POINT('',#676);
#678=EDGE_CURVE('E605',#669,#677,#675,.T.);
#679=ORIENTED_EDGE('',*,*,#678,.T.);
#680=CARTESIAN_POINT('',(28.1781250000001,-12.3031249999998,12.7));
#681=DIRECTION('',(0.,0.,-1.));
#682=DIRECTION('',(1.,0.,0.));
#683=AXIS2_PLACEMENT_3D('',#680,#681,#682);
#684=CIRCLE('',#683,1.666875);
#685=CARTESIAN_POINT('',(26.5112500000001,-12.3031249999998,12.7));
#686=VERTEX_POINT('',#685);
#687=EDGE_CURVE('E604',#677,#686,#684,.T.);
#688=ORIENTED_EDGE('',*,*,#687,.T.);
#689=DIRECTION('',(0.,1.,0.));
#690=VECTOR('',#689,1.);
#691=CARTESIAN_POINT('',(26.5112500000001,-12.3031249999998,12.7));
#692=LINE('',#691,#690);
#693=CARTESIAN_POINT('',(26.5112500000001,-12.0649999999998,12.7));
#694=VERTEX_POINT('',#693);
#695=EDGE_CURVE('E599',#686,#694,#692,.T.);
#696=ORIENTED_EDGE('',*,*,#695,.T.);
#697=CARTESIAN_POINT('',(25.5587500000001,-12.0649999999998,12.7));
#698=DIRECTION('',(0.,0.,1.));
#699=DIRECTION('',(1.,0.,0.));
#700=AXIS2_PLACEMENT_3D('',#697,#698,#699);
#701=CIRCLE('',#700,0.952500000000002);
#702=CARTESIAN_POINT('',(24.6062500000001,-12.0649999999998,12.7));
#703=VERTEX_POINT('',#702);
#704=EDGE_CURVE('E600',#694,#703,#701,.T.);
#705=ORIENTED_EDGE('',*,*,#704,.T.);
#706=DIRECTION('',(0.,-1.,0.));
#707=VECTOR('',#706,1.);
#708=CARTESIAN_POINT('',(24.6062500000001,-12.3031249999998,12.7));
#709=LINE('',#708,#707);
#710=CARTESIAN_POINT('',(24.6062500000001,-12.3031249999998,12.7));
#711=VERTEX_POINT('',#710);
#712=EDGE_CURVE('E289',#703,#711,#709,.T.);
#713=ORIENTED_EDGE('',*,*,#712,.T.);
#714=CARTESIAN_POINT('',(28.1781250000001,-12.3031249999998,12.7));
#715=DIRECTION('',(0.,0.,1.));
#716=DIRECTION('',(1.,0.,0.));
#717=AXIS2_PLACEMENT_3D('',#714,#715,#716);
#718=CIRCLE('',#717,3.571875);
#719=CARTESIAN_POINT('',(31.7500000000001,-12.3031249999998,12.7));
#720=VERTEX_POINT('',#719);
#721=EDGE_CURVE('E285',#711,#720,#718,.T.);
#722=ORIENTED_EDGE('',*,*,#721,.T.);
#723=DIRECTION('',(0.,1.,0.));
#724=VECTOR('',#723,1.);
#725=CARTESIAN_POINT('',(31.7500000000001,-12.3031249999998,12.7));
#726=LINE('',#725,#724);
#727=CARTESIAN_POINT('',(31.7499999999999,13.9700000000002,12.7));
#728=VERTEX_POINT('',#727);
#729=EDGE_CURVE('E272',#720,#728,#726,.T.);
#730=ORIENTED_EDGE('',*,*,#729,.T.);
#731=CARTESIAN_POINT('',(29.8449999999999,13.9700000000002,12.7));
#732=DIRECTION('',(0.,0.,1.));
#733=DIRECTION('',(1.,0.,0.));
#734=AXIS2_PLACEMENT_3D('',#731,#732,#733);
#735=CIRCLE('',#734,1.90499999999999);
#736=CARTESIAN_POINT('',(29.8449999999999,15.8750000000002,12.7));
#737=VERTEX_POINT('',#736);
#738=EDGE_CURVE('E282',#728,#737,#735,.T.);
#739=ORIENTED_EDGE('',*,*,#738,.T.);
#740=DIRECTION('',(-1.,0.,0.));
#741=VECTOR('',#740,1.);
#742=CARTESIAN_POINT('',(29.8449999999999,15.8750000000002,12.7));
#743=LINE('',#742,#741);
#744=CARTESIAN_POINT('',(1.90499999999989,15.875,12.7));
#745=VERTEX_POINT('',#744);
#746=EDGE_CURVE('E590',#737,#745,#743,.T.);
#747=ORIENTED_EDGE('',*,*,#746,.T.);
#748=CARTESIAN_POINT('',(1.9049999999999,13.97,12.7));
#749=DIRECTION('',(0.,0.,1.));
#750=DIRECTION('',(-1.,0.,0.));
#751=AXIS2_PLACEMENT_3D('',#748,#749,#750);
#752=CIRCLE('',#751,1.905);
#753=CARTESIAN_POINT('',(0.,13.97,12.7));
#754=VERTEX_POINT('',#753);
#755=EDGE_CURVE('E625',#745,#754,#752,.T.);
#756=ORIENTED_EDGE('',*,*,#755,.T.);
#757=DIRECTION('',(0.,-1.,0.));
#758=VECTOR('',#757,1.);
#759=CARTESIAN_POINT('',(0.,13.97,12.7));
#760=LINE('',#759,#758);
#761=EDGE_CURVE('E620',#754,#250,#760,.T.);
#762=ORIENTED_EDGE('',*,*,#761,.T.);
#763=ORIENTED_EDGE('',*,*,#251,.T.);
#764=ORIENTED_EDGE('',*,*,#287,.T.);
#765=ORIENTED_EDGE('',*,*,#320,.T.);
#766=ORIENTED_EDGE('',*,*,#351,.T.);
#767=ORIENTED_EDGE('',*,*,#384,.T.);
#768=ORIENTED_EDGE('',*,*,#415,.T.);
#769=ORIENTED_EDGE('',*,*,#446,.T.);
#770=ORIENTED_EDGE('',*,*,#477,.T.);
#771=ORIENTED_EDGE('',*,*,#510,.T.);
#772=ORIENTED_EDGE('',*,*,#541,.T.);
#773=ORIENTED_EDGE('',*,*,#574,.T.);
#774=ORIENTED_EDGE('',*,*,#596,.T.);
#775=EDGE_LOOP('',(#607,#608,#609,#610,#611,#612,#621,#629,#638,#646,#655,#663,#671,#679,#688,
#696,#705,#713,#722,#730,#739,#747,#756,#762,#763,#764,#765,#766,#767,#768,#769,#770,#771,#772,
#773,#774));
#776=FACE_BOUND('',#775,.T.);
#777=ADVANCED_FACE('F287',(#776),#606,.F.);
#778=CARTESIAN_POINT('',(-28.178125,12.303125,-12.7));
#779=DIRECTION('',(0.,0.,-1.));
#780=DIRECTION('',(-1.,0.,0.));
#781=AXIS2_PLACEMENT_3D('',#778,#779,#780);
#782=PLANE('',#781);
#783=ORIENTED_EDGE('',*,*,#33,.F.);
#784=ORIENTED_EDGE('',*,*,#589,.F.);
#785=ORIENTED_EDGE('',*,*,#559,.F.);
#786=ORIENTED_EDGE('',*,*,#527,.F.);
#787=ORIENTED_EDGE('',*,*,#495,.F.);
#788=ORIENTED_EDGE('',*,*,#463,.F.);
#789=ORIENTED_EDGE('',*,*,#432,.F.);
#790=ORIENTED_EDGE('',*,*,#401,.F.);
#791=ORIENTED_EDGE('',*,*,#369,.F.);
#792=ORIENTED_EDGE('',*,*,#337,.F.);
#793=ORIENTED_EDGE('',*,*,#305,.F.);
#794=ORIENTED_EDGE('',*,*,#273,.F.);
#795=ORIENTED_EDGE('',*,*,#234,.F.);
#796=DIRECTION('',(0.,-1.,0.));
#797=VECTOR('',#796,1.);
#798=CARTESIAN_POINT('',(0.,13.97,-12.7));
#799=LINE('',#798,#797);
#800=CARTESIAN_POINT('',(0.,13.97,-12.7));
#801=VERTEX_POINT('',#800);
#802=EDGE_CURVE('E507',#801,#231,#799,.T.);
#803=ORIENTED_EDGE('',*,*,#802,.F.);
#804=CARTESIAN_POINT('',(1.9049999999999,13.97,-12.7));
#805=DIRECTION('',(0.,0.,1.));
#806=DIRECTION('',(-1.,0.,0.));
#807=AXIS2_PLACEMENT_3D('',#804,#805,#806);
#808=CIRCLE('',#807,1.905);
#809=CARTESIAN_POINT('',(1.90499999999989,15.875,-12.7));
#810=VERTEX_POINT('',#809);
#811=EDGE_CURVE('E509',#810,#801,#808,.T.);
#812=ORIENTED_EDGE('',*,*,#811,.F.);
#813=DIRECTION('',(-1.,0.,0.));
#814=VECTOR('',#813,1.);
#815=CARTESIAN_POINT('',(29.8449999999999,15.8750000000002,-12.7));
#816=LINE('',#815,#814);
#817=CARTESIAN_POINT('',(29.8449999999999,15.8750000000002,-12.7));
#818=VERTEX_POINT('',#817);
#819=EDGE_CURVE('E516',#818,#810,#816,.T.);
#820=ORIENTED_EDGE('',*,*,#819,.F.);
#821=CARTESIAN_POINT('',(29.8449999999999,13.9700000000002,-12.7));
#822=DIRECTION('',(0.,0.,1.));
#823=DIRECTION('',(1.,0.,0.));
#824=AXIS2_PLACEMENT_3D('',#821,#822,#823);
#825=CIRCLE('',#824,1.90499999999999);
#826=CARTESIAN_POINT('',(31.7499999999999,13.9700000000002,-12.7));
#827=VERTEX_POINT('',#826);
#828=EDGE_CURVE('E586',#827,#818,#825,.T.);
#829=ORIENTED_EDGE('',*,*,#828,.F.);
#830=DIRECTION('',(0.,1.,0.));
#831=VECTOR('',#830,1.);
#832=CARTESIAN_POINT('',(31.7500000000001,-12.3031249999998,-12.7));
#833=LINE('',#832,#831);
#834=CARTESIAN_POINT('',(31.7500000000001,-12.3031249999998,-12.7));
#835=VERTEX_POINT('',#834);
#836=EDGE_CURVE('E592',#835,#827,#833,.T.);
#837=ORIENTED_EDGE('',*,*,#836,.F.);
#838=CARTESIAN_POINT('',(28.1781250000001,-12.3031249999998,-12.7));
#839=DIRECTION('',(0.,0.,1.));
#840=DIRECTION('',(1.,0.,0.));
#841=AXIS2_PLACEMENT_3D('',#838,#839,#840);
#842=CIRCLE('',#841,3.571875);
#843=CARTESIAN_POINT('',(24.6062500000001,-12.3031249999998,-12.7));
#844=VERTEX_POINT('',#843);
#845=EDGE_CURVE('E298',#844,#835,#842,.T.);
#846=ORIENTED_EDGE('',*,*,#845,.F.);
#847=DIRECTION('',(0.,-1.,0.));
#848=VECTOR('',#847,1.);
#849=CARTESIAN_POINT('',(24.6062500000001,-12.3031249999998,-12.7));
#850=LINE('',#849,#848);
#851=CARTESIAN_POINT('',(24.6062500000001,-12.0649999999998,-12.7));
#852=VERTEX_POINT('',#851);
#853=EDGE_CURVE('E292',#852,#844,#850,.T.);
#854=ORIENTED_EDGE('',*,*,#853,.F.);
#855=CARTESIAN_POINT('',(25.5587500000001,-12.0649999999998,-12.7));
#856=DIRECTION('',(0.,0.,1.));
#857=DIRECTION('',(1.,0.,0.));
#858=AXIS2_PLACEMENT_3D('',#855,#856,#857);
#859=CIRCLE('',#858,0.952500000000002);
#860=CARTESIAN_POINT('',(26.5112500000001,-12.0649999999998,-12.7));
#861=VERTEX_POINT('',#860);
#862=EDGE_CURVE('E540',#861,#852,#859,.T.);
#863=ORIENTED_EDGE('',*,*,#862,.F.);
#864=DIRECTION('',(0.,1.,0.));
#865=VECTOR('',#864,1.);
#866=CARTESIAN_POINT('',(26.5112500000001,-12.3031249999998,-12.7));
#867=LINE('',#866,#865);
#868=CARTESIAN_POINT('',(26.5112500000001,-12.3031249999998,-12.7));
#869=VERTEX_POINT('',#868);
#870=EDGE_CURVE('E539',#869,#861,#867,.T.);
#871=ORIENTED_EDGE('',*,*,#870,.F.);
#872=CARTESIAN_POINT('',(28.1781250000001,-12.3031249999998,-12.7));
#873=DIRECTION('',(0.,0.,-1.));
#874=DIRECTION('',(1.,0.,0.));
#875=AXIS2_PLACEMENT_3D('',#872,#873,#874);
#876=CIRCLE('',#875,1.666875);
#877=CARTESIAN_POINT('',(29.8450000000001,-12.3031249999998,-12.7));
#878=VERTEX_POINT('',#877);
#879=EDGE_CURVE('E534',#878,#869,#876,.T.);
#880=ORIENTED_EDGE('',*,*,#879,.F.);
#881=DIRECTION('',(0.,-1.,0.));
#882=VECTOR('',#881,1.);
#883=CARTESIAN_POINT('',(29.8450000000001,-12.3031249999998,-12.7));
#884=LINE('',#883,#882);
#885=CARTESIAN_POINT('',(29.8449999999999,13.9700000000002,-12.7));
#886=VERTEX_POINT('',#885);
#887=EDGE_CURVE('E535',#886,#878,#884,.T.);
#888=ORIENTED_EDGE('',*,*,#887,.F.);
#889=DIRECTION('',(1.,0.,0.));
#890=VECTOR('',#889,1.);
#891=CARTESIAN_POINT('',(29.8449999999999,13.9700000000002,-12.7));
#892=LINE('',#891,#890);
#893=CARTESIAN_POINT('',(1.9049999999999,13.97,-12.7));
#894=VERTEX_POINT('',#893);
#895=EDGE_CURVE('E528',#894,#886,#892,.T.);
#896=ORIENTED_EDGE('',*,*,#895,.F.);
#897=DIRECTION('',(0.,1.,0.));
#898=VECTOR('',#897,1.);
#899=CARTESIAN_POINT('',(1.9049999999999,13.97,-12.7));
#900=LINE('',#899,#898);
#901=CARTESIAN_POINT('',(1.90500000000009,-12.303125,-12.7));
#902=VERTEX_POINT('',#901);
#903=EDGE_CURVE('E529',#902,#894,#900,.T.);
#904=ORIENTED_EDGE('',*,*,#903,.F.);
#905=CARTESIAN_POINT('',(3.57187500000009,-12.303125,-12.7));
#906=DIRECTION('',(0.,0.,-1.));
#907=DIRECTION('',(-1.,0.,0.));
#908=AXIS2_PLACEMENT_3D('',#905,#906,#907);
#909=CIRCLE('',#908,1.666875);
#910=CARTESIAN_POINT('',(5.23875000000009,-12.303125,-12.7));
#911=VERTEX_POINT('',#910);
#912=EDGE_CURVE('E527',#911,#902,#909,.T.);
#913=ORIENTED_EDGE('',*,*,#912,.F.);
#914=DIRECTION('',(0.,-1.,0.));
#915=VECTOR('',#914,1.);
#916=CARTESIAN_POINT('',(5.23875000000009,-12.303125,-12.7));
#917=LINE('',#916,#915);
#918=CARTESIAN_POINT('',(5.23875000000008,-12.065,-12.7));
#919=VERTEX_POINT('',#918);
#920=EDGE_CURVE('E524',#919,#911,#917,.T.);
#921=ORIENTED_EDGE('',*,*,#920,.F.);
#922=CARTESIAN_POINT('',(6.19125000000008,-12.065,-12.7));
#923=DIRECTION('',(0.,0.,1.));
#924=DIRECTION('',(-1.,0.,0.));
#925=AXIS2_PLACEMENT_3D('',#922,#923,#924);
#926=CIRCLE('',#925,0.9525);
#927=CARTESIAN_POINT('',(7.14375000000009,-12.065,-12.7));
#928=VERTEX_POINT('',#927);
#929=EDGE_CURVE('E525',#928,#919,#926,.T.);
#930=ORIENTED_EDGE('',*,*,#929,.F.);
#931=DIRECTION('',(0.,1.,0.));
#932=VECTOR('',#931,1.);
#933=CARTESIAN_POINT('',(7.14375000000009,-12.3031249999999,-12.7));
#934=LINE('',#933,#932);
#935=CARTESIAN_POINT('',(7.14375000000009,-12.3031249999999,-12.7));
#936=VERTEX_POINT('',#935);
#937=EDGE_CURVE('E513',#936,#928,#934,.T.);
#938=ORIENTED_EDGE('',*,*,#937,.F.);
#939=CARTESIAN_POINT('',(3.57187500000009,-12.303125,-12.7));
#940=DIRECTION('',(0.,0.,1.));
#941=DIRECTION('',(-1.,0.,0.));
#942=AXIS2_PLACEMENT_3D('',#939,#940,#941);
#943=CIRCLE('',#942,3.571875);
#944=EDGE_CURVE('E514',#199,#936,#943,.T.);
#945=ORIENTED_EDGE('',*,*,#944,.F.);
#946=ORIENTED_EDGE('',*,*,#200,.F.);
#947=ORIENTED_EDGE('',*,*,#168,.F.);
#948=ORIENTED_EDGE('',*,*,#136,.F.);
#949=ORIENTED_EDGE('',*,*,#104,.F.);
#950=ORIENTED_EDGE('',*,*,#72,.F.);
#951=EDGE_LOOP('',(#783,#784,#785,#786,#787,#788,#789,#790,#791,#792,#793,#794,#795,#803,#812,
#820,#829,#837,#846,#854,#863,#871,#880,#888,#896,#904,#913,#921,#930,#938,#945,#946,#947,#948,
#949,#950));
#952=FACE_BOUND('',#951,.T.);
#953=ADVANCED_FACE('F431',(#952),#782,.T.);
#954=CARTESIAN_POINT('',(28.1781250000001,-12.3031249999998,12.7));
#955=DIRECTION('',(0.,0.,-1.));
#956=DIRECTION('',(-1.,0.,0.));
#957=AXIS2_PLACEMENT_3D('',#954,#955,#956);
#958=CYLINDRICAL_SURFACE('',#957,3.571875);
#959=ORIENTED_EDGE('',*,*,#845,.T.);
#960=DIRECTION('',(0.,0.,-1.));
#961=VECTOR('',#960,1.);
#962=CARTESIAN_POINT('',(31.7500000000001,-12.3031249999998,12.7));
#963=LINE('',#962,#961);
#964=EDGE_CURVE('E273',#720,#835,#963,.T.);
#965=ORIENTED_EDGE('',*,*,#964,.F.);
#966=ORIENTED_EDGE('',*,*,#721,.F.);
#967=DIRECTION('',(0.,0.,-1.));
#968=VECTOR('',#967,1.);
#969=CARTESIAN_POINT('',(24.6062500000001,-12.3031249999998,12.7));
#970=LINE('',#969,#968);
#971=EDGE_CURVE('E542',#711,#844,#970,.T.);
#972=ORIENTED_EDGE('',*,*,#971,.T.);
#973=EDGE_LOOP('',(#959,#965,#966,#972));
#974=FACE_BOUND('',#973,.T.);
#975=ADVANCED_FACE('F295',(#974),#958,.T.);
#976=CARTESIAN_POINT('',(31.7500000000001,-12.3031249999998,12.7));
#977=DIRECTION('',(-1.,0.,0.));
#978=DIRECTION('',(0.,-1.,0.));
#979=AXIS2_PLACEMENT_3D('',#976,#977,#978);
#980=PLANE('',#979);
#981=ORIENTED_EDGE('',*,*,#836,.T.);
#982=DIRECTION('',(0.,0.,-1.));
#983=VECTOR('',#982,1.);
#984=CARTESIAN_POINT('',(31.7499999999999,13.9700000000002,12.7));
#985=LINE('',#984,#983);
#986=EDGE_CURVE('E280',#728,#827,#985,.T.);
#987=ORIENTED_EDGE('',*,*,#986,.F.);
#988=ORIENTED_EDGE('',*,*,#729,.F.);
#989=ORIENTED_EDGE('',*,*,#964,.T.);
#990=EDGE_LOOP('',(#981,#987,#988,#989));
#991=FACE_BOUND('',#990,.T.);
#992=ADVANCED_FACE('F271',(#991),#980,.F.);
#993=CARTESIAN_POINT('',(29.8449999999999,13.9700000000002,12.7));
#994=DIRECTION('',(0.,0.,-1.));
#995=DIRECTION('',(-1.,0.,0.));
#996=AXIS2_PLACEMENT_3D('',#993,#994,#995);
#997=CYLINDRICAL_SURFACE('',#996,1.90499999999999);
#998=ORIENTED_EDGE('',*,*,#828,.T.);
#999=DIRECTION('',(0.,0.,-1.));
#1000=VECTOR('',#999,1.);
#1001=CARTESIAN_POINT('',(29.8449999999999,15.8750000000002,12.7));
#1002=LINE('',#1001,#1000);
#1003=EDGE_CURVE('E305',#737,#818,#1002,.T.);
#1004=ORIENTED_EDGE('',*,*,#1003,.F.);
#1005=ORIENTED_EDGE('',*,*,#738,.F.);
#1006=ORIENTED_EDGE('',*,*,#986,.T.);
#1007=EDGE_LOOP('',(#998,#1004,#1005,#1006));
#1008=FACE_BOUND('',#1007,.T.);
#1009=ADVANCED_FACE('F622',(#1008),#997,.T.);
#1010=CARTESIAN_POINT('',(29.8449999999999,15.8750000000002,12.7));
#1011=DIRECTION('',(0.,-1.,0.));
#1012=DIRECTION('',(1.,0.,0.));
#1013=AXIS2_PLACEMENT_3D('',#1010,#1011,#1012);
#1014=PLANE('',#1013);
#1015=ORIENTED_EDGE('',*,*,#819,.T.);
#1016=DIRECTION('',(0.,0.,-1.));
#1017=VECTOR('',#1016,1.);
#1018=CARTESIAN_POINT('',(1.90499999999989,15.875,12.7));
#1019=LINE('',#1018,#1017);
#1020=EDGE_CURVE('E576',#745,#810,#1019,.T.);
#1021=ORIENTED_EDGE('',*,*,#1020,.F.);
#1022=ORIENTED_EDGE('',*,*,#746,.F.);
#1023=ORIENTED_EDGE('',*,*,#1003,.T.);
#1024=EDGE_LOOP('',(#1015,#1021,#1022,#1023));
#1025=FACE_BOUND('',#1024,.T.);
#1026=ADVANCED_FACE('F582',(#1025),#1014,.F.);
#1027=CARTESIAN_POINT('',(1.9049999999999,13.97,12.7));
#1028=DIRECTION('',(0.,0.,-1.));
#1029=DIRECTION('',(-1.,0.,0.));
#1030=AXIS2_PLACEMENT_3D('',#1027,#1028,#1029);
#1031=CYLINDRICAL_SURFACE('',#1030,1.905);
#1032=ORIENTED_EDGE('',*,*,#811,.T.);
#1033=DIRECTION('',(0.,0.,-1.));
#1034=VECTOR('',#1033,1.);
#1035=CARTESIAN_POINT('',(0.,13.97,12.7));
#1036=LINE('',#1035,#1034);
#1037=EDGE_CURVE('E580',#754,#801,#1036,.T.);
#1038=ORIENTED_EDGE('',*,*,#1037,.F.);
#1039=ORIENTED_EDGE('',*,*,#755,.F.);
#1040=ORIENTED_EDGE('',*,*,#1020,.T.);
#1041=EDGE_LOOP('',(#1032,#1038,#1039,#1040));
#1042=FACE_BOUND('',#1041,.T.);
#1043=ADVANCED_FACE('F635',(#1042),#1031,.T.);
#1044=CARTESIAN_POINT('',(0.,13.97,12.7));
#1045=DIRECTION('',(1.,0.,0.));
#1046=DIRECTION('',(0.,1.,0.));
#1047=AXIS2_PLACEMENT_3D('',#1044,#1045,#1046);
#1048=PLANE('',#1047);
#1049=ORIENTED_EDGE('',*,*,#257,.F.);
#1050=ORIENTED_EDGE('',*,*,#761,.F.);
#1051=ORIENTED_EDGE('',*,*,#1037,.T.);
#1052=ORIENTED_EDGE('',*,*,#802,.T.);
#1053=EDGE_LOOP('',(#1049,#1050,#1051,#1052));
#1054=FACE_BOUND('',#1053,.T.);
#1055=ADVANCED_FACE('F706',(#1054),#1048,.F.);
#1056=CARTESIAN_POINT('',(3.57187500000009,-12.303125,12.7));
#1057=DIRECTION('',(0.,0.,-1.));
#1058=DIRECTION('',(-1.,0.,0.));
#1059=AXIS2_PLACEMENT_3D('',#1056,#1057,#1058);
#1060=CYLINDRICAL_SURFACE('',#1059,3.571875);
#1061=ORIENTED_EDGE('',*,*,#944,.T.);
#1062=DIRECTION('',(0.,0.,-1.));
#1063=VECTOR('',#1062,1.);
#1064=CARTESIAN_POINT('',(7.14375000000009,-12.3031249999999,12.7));
#1065=LINE('',#1064,#1063);
#1066=EDGE_CURVE('E572',#619,#936,#1065,.T.);
#1067=ORIENTED_EDGE('',*,*,#1066,.F.);
#1068=ORIENTED_EDGE('',*,*,#620,.F.);
#1069=ORIENTED_EDGE('',*,*,#208,.T.);
#1070=EDGE_LOOP('',(#1061,#1067,#1068,#1069));
#1071=FACE_BOUND('',#1070,.T.);
#1072=ADVANCED_FACE('F719',(#1071),#1060,.T.);
#1073=CARTESIAN_POINT('',(7.14375000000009,-12.3031249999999,12.7));
#1074=DIRECTION('',(-1.,0.,0.));
#1075=DIRECTION('',(0.,-1.,0.));
#1076=AXIS2_PLACEMENT_3D('',#1073,#1074,#1075);
#1077=PLANE('',#1076);
#1078=ORIENTED_EDGE('',*,*,#937,.T.);
#1079=DIRECTION('',(0.,0.,-1.));
#1080=VECTOR('',#1079,1.);
#1081=CARTESIAN_POINT('',(7.14375000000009,-12.065,12.7));
#1082=LINE('',#1081,#1080);
#1083=EDGE_CURVE('E569',#627,#928,#1082,.T.);
#1084=ORIENTED_EDGE('',*,*,#1083,.F.);
#1085=ORIENTED_EDGE('',*,*,#628,.F.);
#1086=ORIENTED_EDGE('',*,*,#1066,.T.);
#1087=EDGE_LOOP('',(#1078,#1084,#1085,#1086));
#1088=FACE_BOUND('',#1087,.T.);
#1089=ADVANCED_FACE('F726',(#1088),#1077,.F.);
#1090=CARTESIAN_POINT('',(6.19125000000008,-12.065,12.7));
#1091=DIRECTION('',(0.,0.,-1.));
#1092=DIRECTION('',(-1.,0.,0.));
#1093=AXIS2_PLACEMENT_3D('',#1090,#1091,#1092);
#1094=CYLINDRICAL_SURFACE('',#1093,0.9525);
#1095=ORIENTED_EDGE('',*,*,#929,.T.);
#1096=DIRECTION('',(0.,0.,-1.));
#1097=VECTOR('',#1096,1.);
#1098=CARTESIAN_POINT('',(5.23875000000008,-12.065,12.7));
#1099=LINE('',#1098,#1097);
#1100=EDGE_CURVE('E570',#636,#919,#1099,.T.);
#1101=ORIENTED_EDGE('',*,*,#1100,.F.);
#1102=ORIENTED_EDGE('',*,*,#637,.F.);
#1103=ORIENTED_EDGE('',*,*,#1083,.T.);
#1104=EDGE_LOOP('',(#1095,#1101,#1102,#1103));
#1105=FACE_BOUND('',#1104,.T.);
#1106=ADVANCED_FACE('F738',(#1105),#1094,.T.);
#1107=CARTESIAN_POINT('',(5.23875000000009,-12.303125,12.7));
#1108=DIRECTION('',(1.,0.,0.));
#1109=DIRECTION('',(0.,1.,0.));
#1110=AXIS2_PLACEMENT_3D('',#1107,#1108,#1109);
#1111=PLANE('',#1110);
#1112=ORIENTED_EDGE('',*,*,#920,.T.);
#1113=DIRECTION('',(0.,0.,-1.));
#1114=VECTOR('',#1113,1.);
#1115=CARTESIAN_POINT('',(5.23875000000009,-12.303125,12.7));
#1116=LINE('',#1115,#1114);
#1117=EDGE_CURVE('E562',#644,#911,#1116,.T.);
#1118=ORIENTED_EDGE('',*,*,#1117,.F.);
#1119=ORIENTED_EDGE('',*,*,#645,.F.);
#1120=ORIENTED_EDGE('',*,*,#1100,.T.);
#1121=EDGE_LOOP('',(#1112,#1118,#1119,#1120));
#1122=FACE_BOUND('',#1121,.T.);
#1123=ADVANCED_FACE('F746',(#1122),#1111,.F.);
#1124=CARTESIAN_POINT('',(3.57187500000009,-12.303125,12.7));
#1125=DIRECTION('',(0.,0.,-1.));
#1126=DIRECTION('',(-1.,0.,0.));
#1127=AXIS2_PLACEMENT_3D('',#1124,#1125,#1126);
#1128=CYLINDRICAL_SURFACE('',#1127,1.666875);
#1129=ORIENTED_EDGE('',*,*,#912,.T.);
#1130=DIRECTION('',(0.,0.,-1.));
#1131=VECTOR('',#1130,1.);
#1132=CARTESIAN_POINT('',(1.90500000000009,-12.303125,12.7));
#1133=LINE('',#1132,#1131);
#1134=EDGE_CURVE('E561',#653,#902,#1133,.T.);
#1135=ORIENTED_EDGE('',*,*,#1134,.F.);
#1136=ORIENTED_EDGE('',*,*,#654,.F.);
#1137=ORIENTED_EDGE('',*,*,#1117,.T.);
#1138=EDGE_LOOP('',(#1129,#1135,#1136,#1137));
#1139=FACE_BOUND('',#1138,.T.);
#1140=ADVANCED_FACE('F758',(#1139),#1128,.F.);
#1141=CARTESIAN_POINT('',(1.9049999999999,13.97,12.7));
#1142=DIRECTION('',(-1.,0.,0.));
#1143=DIRECTION('',(0.,-1.,0.));
#1144=AXIS2_PLACEMENT_3D('',#1141,#1142,#1143);
#1145=PLANE('',#1144);
#1146=ORIENTED_EDGE('',*,*,#903,.T.);
#1147=DIRECTION('',(0.,0.,-1.));
#1148=VECTOR('',#1147,1.);
#1149=CARTESIAN_POINT('',(1.9049999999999,13.97,12.7));
#1150=LINE('',#1149,#1148);
#1151=EDGE_CURVE('E556',#661,#894,#1150,.T.);
#1152=ORIENTED_EDGE('',*,*,#1151,.F.);
#1153=ORIENTED_EDGE('',*,*,#662,.F.);
#1154=ORIENTED_EDGE('',*,*,#1134,.T.);
#1155=EDGE_LOOP('',(#1146,#1152,#1153,#1154));
#1156=FACE_BOUND('',#1155,.T.);
#1157=ADVANCED_FACE('F767',(#1156),#1145,.F.);
#1158=CARTESIAN_POINT('',(29.8449999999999,13.9700000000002,12.7));
#1159=DIRECTION('',(0.,1.,0.));
#1160=DIRECTION('',(-1.,0.,0.));
#1161=AXIS2_PLACEMENT_3D('',#1158,#1159,#1160);
#1162=PLANE('',#1161);
#1163=ORIENTED_EDGE('',*,*,#895,.T.);
#1164=DIRECTION('',(0.,0.,-1.));
#1165=VECTOR('',#1164,1.);
#1166=CARTESIAN_POINT('',(29.8449999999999,13.9700000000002,12.7));
#1167=LINE('',#1166,#1165);
#1168=EDGE_CURVE('E554',#669,#886,#1167,.T.);
#1169=ORIENTED_EDGE('',*,*,#1168,.F.);
#1170=ORIENTED_EDGE('',*,*,#670,.F.);
#1171=ORIENTED_EDGE('',*,*,#1151,.T.);
#1172=EDGE_LOOP('',(#1163,#1169,#1170,#1171));
#1173=FACE_BOUND('',#1172,.T.);
#1174=ADVANCED_FACE('F780',(#1173),#1162,.F.);
#1175=CARTESIAN_POINT('',(29.8450000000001,-12.3031249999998,12.7));
#1176=DIRECTION('',(1.,0.,0.));
#1177=DIRECTION('',(0.,1.,0.));
#1178=AXIS2_PLACEMENT_3D('',#1175,#1176,#1177);
#1179=PLANE('',#1178);
#1180=ORIENTED_EDGE('',*,*,#887,.T.);
#1181=DIRECTION('',(0.,0.,-1.));
#1182=VECTOR('',#1181,1.);
#1183=CARTESIAN_POINT('',(29.8450000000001,-12.3031249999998,12.7));
#1184=LINE('',#1183,#1182);
#1185=EDGE_CURVE('E552',#677,#878,#1184,.T.);
#1186=ORIENTED_EDGE('',*,*,#1185,.F.);
#1187=ORIENTED_EDGE('',*,*,#678,.F.);
#1188=ORIENTED_EDGE('',*,*,#1168,.T.);
#1189=EDGE_LOOP('',(#1180,#1186,#1187,#1188));
#1190=FACE_BOUND('',#1189,.T.);
#1191=ADVANCED_FACE('F789',(#1190),#1179,.F.);
#1192=CARTESIAN_POINT('',(28.1781250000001,-12.3031249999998,12.7));
#1193=DIRECTION('',(0.,0.,-1.));
#1194=DIRECTION('',(-1.,0.,0.));
#1195=AXIS2_PLACEMENT_3D('',#1192,#1193,#1194);
#1196=CYLINDRICAL_SURFACE('',#1195,1.666875);
#1197=ORIENTED_EDGE('',*,*,#879,.T.);
#1198=DIRECTION('',(0.,0.,-1.));
#1199=VECTOR('',#1198,1.);
#1200=CARTESIAN_POINT('',(26.5112500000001,-12.3031249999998,12.7));
#1201=LINE('',#1200,#1199);
#1202=EDGE_CURVE('E546',#686,#869,#1201,.T.);
#1203=ORIENTED_EDGE('',*,*,#1202,.F.);
#1204=ORIENTED_EDGE('',*,*,#687,.F.);
#1205=ORIENTED_EDGE('',*,*,#1185,.T.);
#1206=EDGE_LOOP('',(#1197,#1203,#1204,#1205));
#1207=FACE_BOUND('',#1206,.T.);
#1208=ADVANCED_FACE('F800',(#1207),#1196,.F.);
#1209=CARTESIAN_POINT('',(26.5112500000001,-12.3031249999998,12.7));
#1210=DIRECTION('',(-1.,0.,0.));
#1211=DIRECTION('',(0.,-1.,0.));
#1212=AXIS2_PLACEMENT_3D('',#1209,#1210,#1211);
#1213=PLANE('',#1212);
#1214=ORIENTED_EDGE('',*,*,#870,.T.);
#1215=DIRECTION('',(0.,0.,-1.));
#1216=VECTOR('',#1215,1.);
#1217=CARTESIAN_POINT('',(26.5112500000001,-12.0649999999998,12.7));
#1218=LINE('',#1217,#1216);
#1219=EDGE_CURVE('E547',#694,#861,#1218,.T.);
#1220=ORIENTED_EDGE('',*,*,#1219,.F.);
#1221=ORIENTED_EDGE('',*,*,#695,.F.);
#1222=ORIENTED_EDGE('',*,*,#1202,.T.);
#1223=EDGE_LOOP('',(#1214,#1220,#1221,#1222));
#1224=FACE_BOUND('',#1223,.T.);
#1225=ADVANCED_FACE('F809',(#1224),#1213,.F.);
#1226=CARTESIAN_POINT('',(25.5587500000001,-12.0649999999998,12.7));
#1227=DIRECTION('',(0.,0.,-1.));
#1228=DIRECTION('',(-1.,0.,0.));
#1229=AXIS2_PLACEMENT_3D('',#1226,#1227,#1228);
#1230=CYLINDRICAL_SURFACE('',#1229,0.952500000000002);
#1231=ORIENTED_EDGE('',*,*,#862,.T.);
#1232=DIRECTION('',(0.,0.,-1.));
#1233=VECTOR('',#1232,1.);
#1234=CARTESIAN_POINT('',(24.6062500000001,-12.0649999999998,12.7));
#1235=LINE('',#1234,#1233);
#1236=EDGE_CURVE('E543',#703,#852,#1235,.T.);
#1237=ORIENTED_EDGE('',*,*,#1236,.F.);
#1238=ORIENTED_EDGE('',*,*,#704,.F.);
#1239=ORIENTED_EDGE('',*,*,#1219,.T.);
#1240=EDGE_LOOP('',(#1231,#1237,#1238,#1239));
#1241=FACE_BOUND('',#1240,.T.);
#1242=ADVANCED_FACE('F816',(#1241),#1230,.T.);
#1243=CARTESIAN_POINT('',(24.6062500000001,-12.3031249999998,12.7));
#1244=DIRECTION('',(1.,0.,0.));
#1245=DIRECTION('',(0.,1.,0.));
#1246=AXIS2_PLACEMENT_3D('',#1243,#1244,#1245);
#1247=PLANE('',#1246);
#1248=ORIENTED_EDGE('',*,*,#853,.T.);
#1249=ORIENTED_EDGE('',*,*,#971,.F.);
#1250=ORIENTED_EDGE('',*,*,#712,.F.);
#1251=ORIENTED_EDGE('',*,*,#1236,.T.);
#1252=EDGE_LOOP('',(#1248,#1249,#1250,#1251));
#1253=FACE_BOUND('',#1252,.T.);
#1254=ADVANCED_FACE('F828',(#1253),#1247,.F.);
#1255=CLOSED_SHELL('',(#60,#91,#124,#155,#188,#219,#261,#292,#325,#356,#389,#420,#451,#482,#515,
#546,#579,#601,#777,#953,#975,#992,#1009,#1026,#1043,#1055,#1072,#1089,#1106,#1123,#1140,#1157,
#1174,#1191,#1208,#1225,#1242,#1254));
#1256=MANIFOLD_SOLID_BREP('B2',#1255);
#1257=ADVANCED_BREP_SHAPE_REPRESENTATION('',(#18,#1256),#14);
#1258=SHAPE_DEFINITION_REPRESENTATION(#9,#1257);
ENDSEC;
END-ISO-10303-21;
